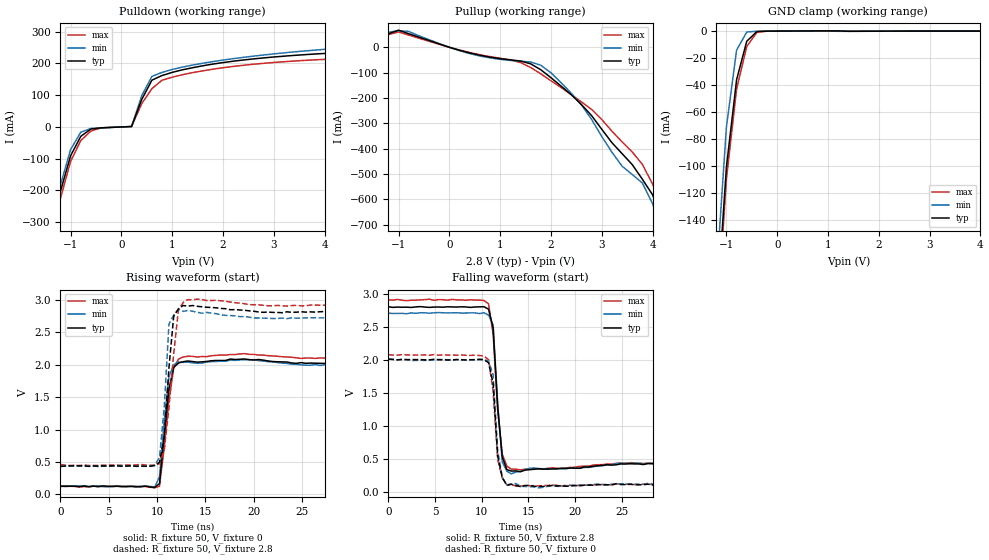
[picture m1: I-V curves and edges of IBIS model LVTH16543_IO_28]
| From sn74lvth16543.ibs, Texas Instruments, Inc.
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|  Model LVTH16543 IO_28
[Model]   LVTH16543_IO_28
Model_type  I/O
Polarity   Non-Inverting
Enable   Active-Low
Vinl = 0.8V
Vinh = 2.0V
Vmeas = 1.5V
Cref = 50pF
Rref = 500
Vref = 0
| variable   typ   min   max
C_comp   10pf   NA   NA
[Temperature Range]   40   -25   100
| Ambient temperatur   25   -40   85
[Voltage range]   2.8   2.7   2.9
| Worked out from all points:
|   slope of the pulldown table from 0 to 0.42 V, typ, clamps not added: 4.54 ohm
|   slope of the pullup table from 0 to 0.42 V, typ, clamps not added: 18.2 ohm
|   GND clamp passes 1 mA (typ) near -0.42 V on its own axis
|   rising waveform, R_fixture 50, V_fixture 0: 20-80 % time 766ps typ, 717ps min, 891ps max; typ from 0.126 V to 2.01 V
|   falling waveform, R_fixture 50, V_fixture 2.8: 20-80 % time 677ps typ, 631ps min, 739ps max; typ from 2.81 V to 0.43 V
|   rising waveform, R_fixture 50, V_fixture 2.8: 20-80 % time 709ps typ, 633ps min, 957ps max; typ from 0.429 V to 2.8 V
|   falling waveform, R_fixture 50, V_fixture 0: 20-80 % time 571ps typ, 580ps min, 645ps max; typ from 2.02 V to 0.115 V
[Pullup]
|   Voltage   I(typ)   I(min)   I(max)
-5V       71.68uA    70.23uA    70.37uA
-2.6V     61.42uA    58.61uA    61.53uA
-2.4V     57.5mA     58.24uA    53.99mA
-2V       53.92mA    57.64uA    48.63mA
-1.8V     53.23mA    57.09mA    49.41mA
-1V       67.63mA    65.55mA    60.85mA
1.8V      -88.55mA   -70.76mA   -104.8mA
2.6V      -226.1mA   -226.9mA   -215.6mA
3.6V      -463.1mA   -502.4mA   -413.3mA
4.2V      -681.8mA   -735.2mA   -636.5mA
4.4V      -791.1mA   -854.4mA   -729.4mA
10V       -3.853A    -4.193A    -3.394A
[Pulldown]
|   Voltage   I(typ)   I(min)   I(max)
-5V       -3.718A    -4.049A    -3.392A
-1.4V     -350.6mA   -345.3mA   -372.4mA
-1V       -90.72mA   -71.05mA   -108.6mA
-800mV    -29.6mA    -16.67mA   -42.89mA
-400mV    -2.754mA   -3.177mA   -3.112mA
200mV     1.357mA    1.517mA    1.266mA
600mV     147.1mA    159mA      120.4mA
1V        171.7mA    180.9mA    156.5mA
5.4V      243.5mA    267mA      221.5mA
6.4V      260.2mA    311.3mA    231mA
8V        313.1mA    380.6mA    264.6mA
10V       381.5mA    457.4mA    310.2mA
[GND Clamp]
|   Voltage   I(typ)   I(min)   I(max)
-5V       -3.531A    -3.847A    -3.351A
-1.2V     -212.4mA   -183.2mA   -223.7mA
-1V       -100.6mA   -70.8mA    -109.4mA
-800mV    -36.02mA   -14.09mA   -42.89mA
-600mV    -7.518mA   -681.5uA   -11.42mA
-400mV    -324.5uA   -114.3uA   -946.4uA
-200mV    -43.37uA   -55.68uA   -45.2uA
5V        38.16nA    53.92nA    60.75nA
[ramp]
| variable   typ   min   max
dV/dt_r   1.170E+00/7.370E-10  1.152E+00/6.280E-10  1.218E+00/8.120E-10
dV/dt_f   1.458E+00/5.770E-10  1.398E+00/4.580E-10  1.518E+00/6.610E-10
R_load = 50
[Rising Waveform]
R_fixture = 50
V_fixture = 0
V_fixture_min = 0
V_fixture_max = 0
C_fixture = 0
L_fixture = 0
|   Time   V(typ)   V(min)   V(max)
0s        125.9mV    117.5mV    121.8mV
9.766ns   106.1mV    112.8mV    98.57mV
10.25ns   163.4mV    270.2mV    123.9mV
10.74ns   893.6mV    1.129V     718.9mV
11.23ns   1.625V     1.815V     1.45V
11.72ns   1.959V     2.002V     1.949V
12.7ns    2.048V     2.037V     2.122V
19.04ns   2.09V      2.079V     2.173V
26.86ns   2.023V     1.989V     2.106V
49.71ns   2.012V     2.003V     2.076V
[Falling Waveform]
R_fixture = 50
V_fixture = 2.8
V_fixture_min = 2.7
V_fixture_max = 2.9
C_fixture = 0
L_fixture = 0
|   Time   V(typ)   V(min)   V(max)
0s        2.808V     2.711V     2.914V
10.74ns   2.771V     2.681V     2.852V
11.23ns   2.488V     2.533V     2.395V
11.72ns   1.288V     1.351V     1.236V
12.21ns   540.8mV    463.6mV    578.9mV
12.7ns    345mV      322.6mV    397.7mV
13.18ns   323.3mV    281.1mV    353.4mV
15.14ns   344.4mV    364.8mV    358.7mV
24.9ns    431.1mV    441.9mV    445mV
49.71ns   430mV      431.8mV    443.1mV
[Rising Waveform]
R_fixture = 50
V_fixture = 2.8
V_fixture_min = 2.7
V_fixture_max = 2.9
C_fixture = 0
L_fixture = 0
|   Time   V(typ)   V(min)   V(max)
0s        428.8mV    431.8mV    459.6mV
8.789ns   432mV      432mV      451.4mV
10.25ns   494.5mV    566.4mV    470.1mV
10.74ns   877.1mV    1.333V     681mV
11.23ns   1.955V     2.627V     1.338V
11.72ns   2.747V     2.768V     2.169V
12.21ns   2.864V     2.859V     2.848V
13.18ns   2.907V     2.84V      3.008V
20.02ns   2.828V     2.723V     2.928V
49.71ns   2.803V     2.708V     2.902V
[Falling Waveform]
R_fixture = 50
V_fixture = 0
V_fixture_min = 0
V_fixture_max = 0
C_fixture = 0
L_fixture = 0
|   Time   V(typ)   V(min)   V(max)
0s        2.018V     2.011V     2.082V
9.277ns   2.008V     2.003V     2.075V
10.74ns   1.962V     1.985V     2.008V
11.23ns   1.648V     1.776V     1.531V
11.72ns   553.6mV    637.1mV    496.1mV
12.21ns   224mV      229.3mV    218.8mV
12.7ns    107.7mV    114.1mV    113.8mV
16.11ns   89.11mV    69.43mV    99.03mV
24.41ns   130.9mV    131.2mV    123.9mV
49.71ns   115.4mV    137mV      120.9mV
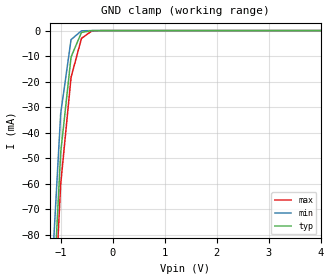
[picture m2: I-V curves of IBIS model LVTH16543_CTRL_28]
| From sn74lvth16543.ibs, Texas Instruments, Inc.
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|   Model LVTH16543 Input CTRL_28
[Model]   LVTH16543_CTRL_28
Model_type  Input
Polarity   Inverting
Vinl = 0.8V
Vinh = 2.0V
| variable   typ   min   max
C_comp   4pf   NA   NA
[Temperature Range]   40   -25   100
| Ambient temperature   25   -40   85
[Voltage range]   2.8   2.7   2.9
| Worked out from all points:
|   GND clamp passes 1 mA (typ) near -0.61 V on its own axis
[GND Clamp]
|   Voltage   I(typ)   I(min)   I(max)
-5V       -2.536A    -2.937A    -2.213A
-1.2V     -128.1mA   -106.8mA   -142mA
-1V       -47.84mA   -32.54mA   -60.24mA
-800mV    -10.33mA   -3.526mA   -18.26mA
-600mV    -729.3uA   -89.46uA   -3.06mA
-400mV    -3.145uA   -186.5nA   -122.8uA
-200mV    -2.271nA   -43.08nA   -362.2nA
5V        209.8pA    1.976uA    420.1pA
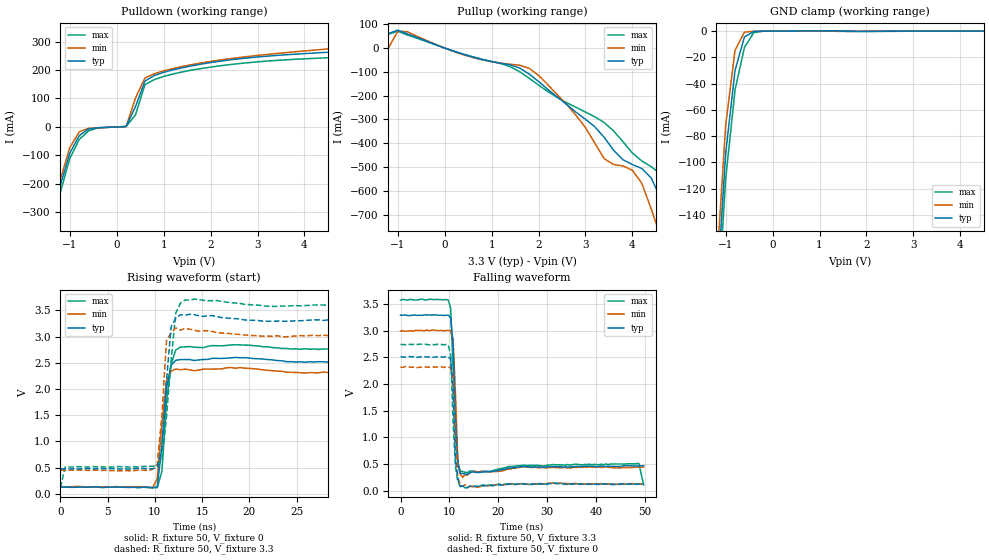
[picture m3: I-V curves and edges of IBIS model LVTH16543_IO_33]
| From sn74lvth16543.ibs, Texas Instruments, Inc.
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|  Model LVTH16543 IO_33
[Model]   LVTH16543_IO_33
Model_type  I/O
Polarity   Non-Inverting
Enable   Active-Low
Vinl = 0.8V
Vinh = 2.0V
Vmeas = 1.5V
Cref = 50pF
Rref = 500
Vref = 0
| variable   typ   min   max
C_comp   10pf   NA   NA
[Temperature Range]   40   -25   100
| Ambient temperatur   25   -40   85
[Voltage range]   3.3   3.0   3.6
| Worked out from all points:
|   slope of the pulldown table from 0 to 0.495 V, typ, clamps not added: 4.33 ohm
|   slope of the pullup table from 0 to 0.495 V, typ, clamps not added: 15.5 ohm
|   GND clamp passes 1 mA (typ) near -0.44 V on its own axis
|   rising waveform, R_fixture 50, V_fixture 0: 20-80 % time 704ps typ, 684ps min, 722ps max; typ from 0.123 V to 2.51 V
|   falling waveform, R_fixture 50, V_fixture 3.3: 20-80 % time 674ps typ, 650ps min, 963ps max; typ from 3.29 V to 0.471 V
|   rising waveform, R_fixture 50, V_fixture 3.3: 20-80 % time 692ps typ, 623ps min, 1.07ns max; typ from 0.476 V to 3.29 V
|   falling waveform, R_fixture 50, V_fixture 0: 20-80 % time 615ps typ, 669ps min, 732ps max; typ from 2.52 V to 0.122 V
[Pullup]
|   Voltage   I(typ)   I(min)   I(max)
-5V       85.9uA     79.77uA    88.73uA
-1.6V     74.4uA     66.12uA    79.61uA
-1.4V     58.85mA    65.79uA    79.26uA
-1.2V     60.88mA    64.76uA    58.23mA
-800mV    60.26mA    69.01mA    55.01mA
1.8V      -109mA     -84.78mA   -126.7mA
3.4V      -375.6mA   -465.2mA   -313.4mA
4V        -489.8mA   -513.8mA   -441.2mA
4.6V      -630.4mA   -791.9mA   -529.3mA
4.8V      -733.6mA   -908.6mA   -594.5mA
5.2V      -939.8mA   -1.142A    -772.2mA
10V       -3.415A    -3.941A    -2.946A
[Pulldown]
|   Voltage   I(typ)   I(min)   I(max)
-5V       -3.777A    -4.056A    -3.408A
-1.4V     -351.5mA   -345.8mA   -377.4mA
-1.2V     -203.6mA   -183.5mA   -228.2mA
-1V       -91.83mA   -72.18mA   -110.7mA
-800mV    -30.5mA    -17.3mA    -44.23mA
-400mV    -2.849mA   -3.239mA   -3.347mA
200mV     1.39mA     1.524mA    1.34mA
400mV     71.8mA     101.9mA    42.63mA
600mV     161.2mA    172.1mA    148.5mA
1V        191.7mA    197.2mA    177.4mA
7V        298.6mA    350.2mA    267.5mA
10V       360.4mA    420.4mA    320.9mA
[GND Clamp]
|   Voltage   I(typ)   I(min)   I(max)
-5V       -3.695A    -4.021A    -3.373A
-1.2V     -205.6mA   -184.5mA   -228.2mA
-1V       -93.28mA   -71.75mA   -112.5mA
-800mV    -29.85mA   -14.61mA   -44.82mA
-600mV    -4.456mA   -728.4uA   -12.39mA
-400mV    -148.8uA   -122.5uA   -1.157mA
-200mV    -52.48uA   -60.15uA   -52.9uA
5V        28.78nA    54.49nA    66.83nA
[ramp]
| variable   typ   min   max
dV/dt_r   1.470E+00/6.200E-10  1.344E+00/5.390E-10  1.620E+00/6.970E-10
dV/dt_f   1.740E+00/6.470E-10  1.572E+00/4.860E-10  1.902E+00/7.530E-10
R_load = 50
[Rising Waveform]
R_fixture = 50
V_fixture = 0
V_fixture_min = 0
V_fixture_max = 0
C_fixture = 0
L_fixture = 0
|   Time   V(typ)   V(min)   V(max)
0s        123.4mV    137.6mV    125mV
9.766ns   111.4mV    113.1mV    119.8mV
10.25ns   134.9mV    287.8mV    114mV
10.74ns   912.3mV    1.318V     423.7mV
11.23ns   2.019V     2.161V     1.749V
11.72ns   2.457V     2.344V     2.479V
12.21ns   2.549V     2.382V     2.746V
12.7ns    2.562V     2.368V     2.8V
18.55ns   2.603V     2.397V     2.845V
49.71ns   2.513V     2.324V     2.741V
[Falling Waveform]
R_fixture = 50
V_fixture = 3.3
V_fixture_min = 3.0
V_fixture_max = 3.6
C_fixture = 0
L_fixture = 0
|   Time   V(typ)   V(min)   V(max)
0s        3.293V     2.997V     3.575V
9.766ns   3.291V     3.01V      3.574V
10.25ns   3.244V     2.993V     3.42V
10.74ns   2.742V     2.842V     2.313V
11.23ns   1.348V     1.83V      1.051V
11.72ns   534.4mV    538.6mV    505.2mV
12.21ns   328.4mV    316.2mV    369mV
24.9ns    450.3mV    451.5mV    476.2mV
48.73ns   466.2mV    446.8mV    513.6mV
49.71ns   470.9mV    443.7mV    111.6mV
[Rising Waveform]
R_fixture = 50
V_fixture = 3.3
V_fixture_min = 3.0
V_fixture_max = 3.6
C_fixture = 0
L_fixture = 0
|   Time   V(typ)   V(min)   V(max)
0s        476.4mV    447.1mV    114.6mV
488.3ps   473.3mV    446.9mV    507.4mV
9.766ns   476.5mV    465.9mV    526mV
10.25ns   509mV      564.9mV    530.9mV
10.74ns   857.1mV    1.496V     648.8mV
11.23ns   2.161V     2.928V     1.477V
11.72ns   3.193V     3.071V     2.556V
12.21ns   3.346V     3.166V     3.446V
13.18ns   3.409V     3.158V     3.699V
49.71ns   3.294V     3.001V     3.584V
[Falling Waveform]
R_fixture = 50
V_fixture = 0
V_fixture_min = 0
V_fixture_max = 0
C_fixture = 0
L_fixture = 0
|   Time   V(typ)   V(min)   V(max)
0s        2.519V     2.316V     2.744V
9.766ns   2.509V     2.322V     2.731V
10.25ns   2.468V     2.306V     2.553V
10.74ns   1.878V     2.145V     1.31V
11.23ns   577.9mV    1.084V     447.7mV
11.72ns   224.3mV    247.3mV    166.8mV
12.21ns   77.21mV    108mV      86.21mV
15.63ns   84.23mV    59.97mV    87.43mV
24.9ns    125mV      135.8mV    134mV
49.71ns   122.2mV    132.3mV    130.8mV
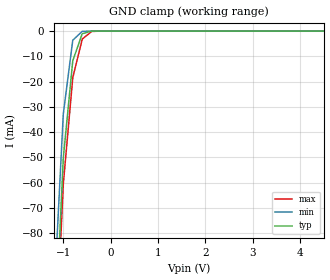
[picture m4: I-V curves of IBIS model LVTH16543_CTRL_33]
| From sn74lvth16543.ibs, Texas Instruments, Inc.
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|   Model LVTH16543 Input CTRL_33
[Model]   LVTH16543_CTRL_33
Model_type  Input
Polarity   Inverting
Vinl = 0.8V
Vinh = 2.0V
| variable   typ   min   max
C_comp   4pf   NA   NA
[Temperature Range]   40   -25   100
| Ambient temperature   25   -40   85
[Voltage range]   3.3   3.0   3.6
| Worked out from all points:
|   GND clamp passes 1 mA (typ) near -0.59 V on its own axis
[GND Clamp]
|   Voltage   I(typ)   I(min)   I(max)
-5V       -2.465A    -2.922A    -2.194A
-1.2V     -131.1mA   -107.3mA   -142.1mA
-1V       -50.28mA   -32.82mA   -60.59mA
-800mV    -11.76mA   -3.61mA    -18.5mA
-600mV    -1.037mA   -91.87uA   -3.155mA
-400mV    -6.455uA   -220.7nA   -133.7uA
-200mV    -6.069nA   -52.03nA   -412.3nA
5V        120.4pA    2.58uA     444.1pA
